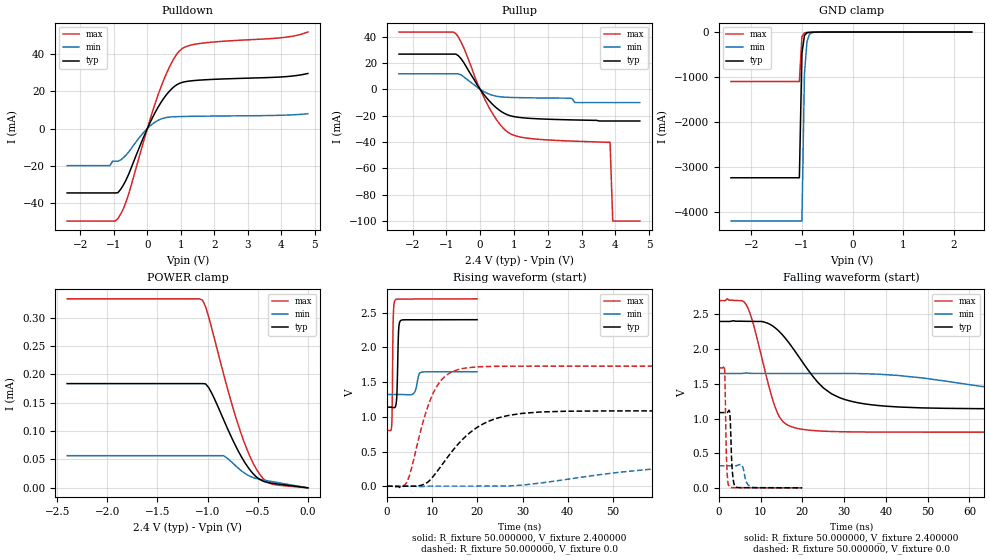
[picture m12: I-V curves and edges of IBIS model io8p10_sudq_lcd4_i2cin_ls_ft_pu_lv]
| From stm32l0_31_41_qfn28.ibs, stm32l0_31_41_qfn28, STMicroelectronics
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|   Model io8p10_sudq_lcd4_i2cin_ls_ft_pu_lv
[Model]  io8p10_sudq_lcd4_i2cin_ls_ft_pu_lv
Model_type I/O
Polarity   Non-Inverting
Enable   Active-Low
Vinl =   0.720000V
Vinh =   1.680000V
Vmeas =  1.200000V
Cref =   50.000000pF
Rref =   100.000000M
Vref =   0.0V
C_comp   2.470900pF   2.435200pF   2.490500pF
[Temperature Range]   25.000000   0.105000k   -40.000000
[Pullup Reference]   2.400000V   1.650000V   2.700000V
[Pulldown Reference]   0.0V   0.0V   0.0V
[POWER Clamp Reference]   2.400000V   1.650000V   2.700000V
[GND Clamp Reference]   0.0V   0.0V   0.0V
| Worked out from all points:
|   slope of the pulldown table from 0 to 0.36 V, typ, clamps not added: 28.5 ohm
|   slope of the pullup table from 0 to 0.36 V, typ, clamps not added: 32.2 ohm
|   GND clamp passes 1 mA (typ) near -0.64 V on its own axis
|   rising waveform, R_fixture 50.000000, V_fixture 2.400000: 20-80 % time 282ps typ, 633ps min, 192ps max; typ from 1.14 V to 2.4 V
|   rising waveform, R_fixture 50.000000, V_fixture 0.0: 20-80 % time 9.33ns typ, 24.7ns min, 4.79ns max; typ from 0.001 V to 1.09 V
|   falling waveform, R_fixture 50.000000, V_fixture 2.400000: 20-80 % time 10.1ns typ, 27.9ns min, 4.93ns max; typ from 2.4 V to 1.14 V
|   falling waveform, R_fixture 50.000000, V_fixture 0.0: 20-80 % time 459ps typ, 825ps min, 363ps max; typ from 1.09 V to 0.001 V
[Pulldown]
|Voltage   I(typ)   I(min)   I(max)
-2.4V     -34.71mA   -20mA      -49.82mA
-1.12V    -34.71mA   -20mA      -49.82mA
-1.04V    -34.71mA   -17.6mA    -49.82mA
-880mV    -34.55mA   -17.6mA    -48.46mA
-560mV    -24.65mA   -12.68mA   -35.33mA
0V        0A         0A         0A
400mV     13.84mA    5.066mA    22.03mA
720mV     21.25mA    6.254mA    35.26mA
1.04V     24.83mA    6.464mA    43.02mA
1.6V      26.11mA    6.627mA    45.88mA
4V        27.76mA    7.125mA    48.87mA
4.8V      29.64mA    7.94mA     51.96mA
[Pullup]
|Voltage   I(typ)   I(min)   I(max)
-2.4V     26.83mA    11.83mA    43.61mA
-720mV    26.83mA    11.83mA    42.44mA
-480mV    20.19mA    9.416mA    31.24mA
-160mV    6.617mA    3.074mA    9.467mA
240mV     -7.917mA   -3.299mA   -12.65mA
560mV     -15.67mA   -5.497mA   -25.76mA
880mV     -19.92mA   -6.062mA   -33.51mA
1.68V     -22.29mA   -6.449mA   -37.81mA
2.8V      -23.2mA    -10mA      -39.35mA
3.84V     -24mA      -10mA      -40.2mA
3.92V     -24mA      -10mA      -100mA
4.72V     -24mA      -10mA      -100mA
[GND_clamp]
|Voltage   I(typ)   I(min)   I(max)
-2.4V     -3.237A    -4.197A    -1.1A
-1.05V    -3.237A    -4.197A    -1.1A
-1V       -475.5mA   -4.197A    -104.1mA
-950mV    -76.08mA   -935.1mA   -18.44mA
-900mV    -16.57mA   -212.6mA   -9.263mA
-850mV    -6.62mA    -50.88mA   -6.764mA
-800mV    -4.092mA   -13.84mA   -4.994mA
-650mV    -1.07mA    -1.21mA    -1.175mA
2.35V     0A         0A         0A
[POWER_clamp]
|Voltage   I(typ)   I(min)   I(max)
-2.4V     183.7uA    56.67uA    333uA
-1.05V    183.7uA    56.67uA    330.8uA
-1.02V    183.2uA    56.67uA    319.3uA
-960mV    167.4uA    56.67uA    282.2uA
-840mV    120.1uA    56.67uA    200.3uA
-750mV    84.75uA    43.78uA    142.9uA
-690mV    63.55uA    34.11uA    108.5uA
-600mV    37.04uA    22.45uA    64.63uA
-510mV    18.73uA    16.35uA    31.91uA
-450mV    12.06uA    14.02uA    17.25uA
-360mV    8.154uA    11.11uA    6.782uA
0V        0A         0A         0A
[Ramp]
| variable   typ   min   max
dV/dt_r  0.65095/9.32063n   0.19037/24.70091n   1.03799/4.78137n
dV/dt_f  0.75618/10.08805n   0.19644/27.87132n   1.13779/4.92122n
R_load = 50.000000
[Rising Waveform]
R_fixture= 50.000000
V_fixture= 2.400000
V_fixture_min= 1.650000
V_fixture_max= 2.700000
|time   V(typ)   V(min)   V(max)
0s        1.14V      1.323V     803.7mV
1.041ns   1.139V     1.323V     871.1mV
1.161ns   1.138V     1.323V     1.195V
1.361ns   1.135V     1.323V     2.358V
1.762ns   1.137V     1.323V     2.679V
2.202ns   1.344V     1.323V     2.696V
2.603ns   2.276V     1.323V     2.697V
2.963ns   2.383V     1.323V     2.697V
7.487ns   2.399V     1.64V      2.699V
19.94ns   2.4V       1.65V      2.7V
[Rising Waveform]
R_fixture= 50.000000
V_fixture= 0.0
V_fixture_min= 0.0
V_fixture_max= 0.0
|time   V(typ)   V(min)   V(max)
0s        880uV      1.328mV    513.7uV
4.505ns   1.766mV    1.425mV    73.49mV
8.509ns   39.97mV    1.585mV    1.044V
11.51ns   250.5mV    2.321mV    1.488V
14.01ns   470.7mV    2.317mV    1.636V
18.02ns   753.8mV    2.334mV    1.709V
26.53ns   1.016V     4.385mV    1.73V
39.54ns   1.081V     97.11mV    1.73V
84.08ns   1.086V     308.5mV    1.73V
249.2ns   1.086V     318.6mV    1.73V
[Falling Waveform]
R_fixture= 50.000000
V_fixture= 2.400000
V_fixture_min= 1.650000
V_fixture_max= 2.700000
|time   V(typ)   V(min)   V(max)
0s        2.4V       1.65V      2.7V
6.507ns   2.402V     1.657V     2.645V
8.008ns   2.401V     1.651V     2.412V
14.01ns   2.281V     1.65V      1.082V
16.02ns   2.15V      1.65V      922.3mV
21.02ns   1.728V     1.65V      835.9mV
29.03ns   1.298V     1.65V      810.3mV
43.54ns   1.165V     1.617V     804.1mV
92.59ns   1.14V      1.351V     803.7mV
249.2ns   1.14V      1.323V     803.7mV
[Falling Waveform]
R_fixture= 50.000000
V_fixture= 0.0
V_fixture_min= 0.0
V_fixture_max= 0.0
|time   V(typ)   V(min)   V(max)
0s        1.086V     318.6mV    1.73V
1.321ns   1.086V     318.6mV    1.744V
1.441ns   1.086V     318.6mV    1.582V
1.882ns   1.085V     318.6mV    331.5mV
2.442ns   1.119V     318.6mV    21.27mV
2.683ns   1.013V     318.6mV    9.074mV
3.203ns   249.6mV    318.4mV    3.745mV
3.884ns   18.56mV    318.2mV    3.348mV
7.928ns   2.809mV    9.521mV    2.057mV
19.94ns   880uV      1.328mV    513.7uV
